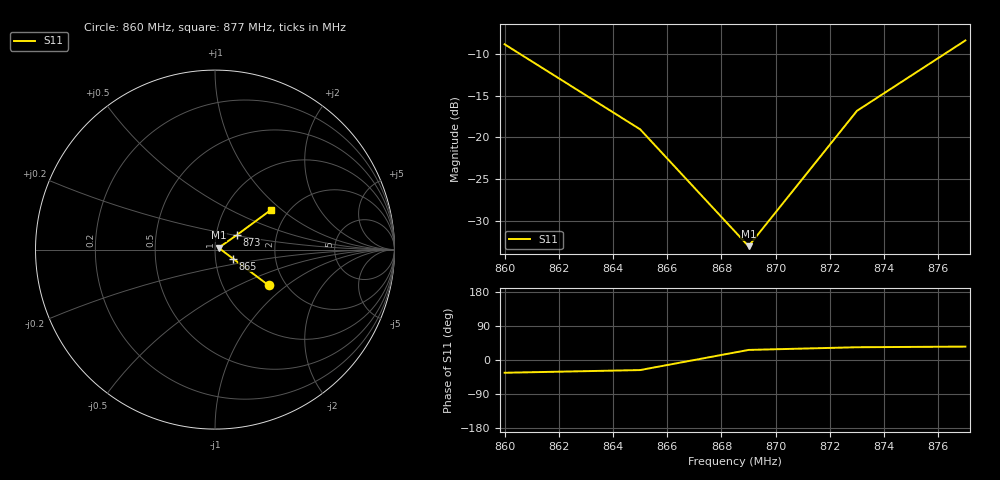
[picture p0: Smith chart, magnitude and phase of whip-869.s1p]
! Hand-written fixture: a 869 MHz whip, real/imaginary in MHz.
! Second comment line
# MHz S RI R 50
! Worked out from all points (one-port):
!   5 points, 860 MHz to 877 MHz, reference 50 ohm
!   lowest |S11| = -33.0 dB at 869 MHz (marker M1), VSWR 1.05, Z = 52 + j1.04 ohm
!   |S11| at or under -10 dB: 860.56 MHz to 876.24 MHz (15.68 MHz wide, 1.81 % of centre)
!   S11 on the Smith chart (normalised r, x): 860 MHz: 1.64, -0.75; 865 MHz: 1.22, -0.12; 873 MHz: 1.25, +0.20; 877 MHz: 1.63, +0.84
860  0.3 -0.2
865  0.1 -0.05
869  0.02 0.01
873  0.12 0.08
877  0.31 0.22
